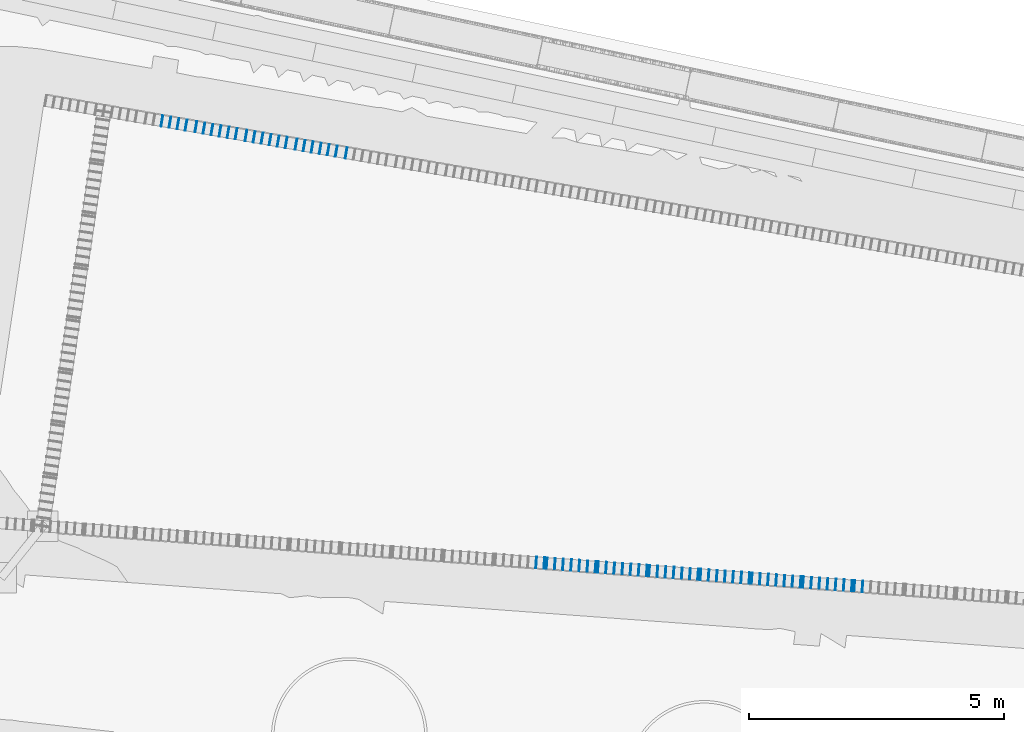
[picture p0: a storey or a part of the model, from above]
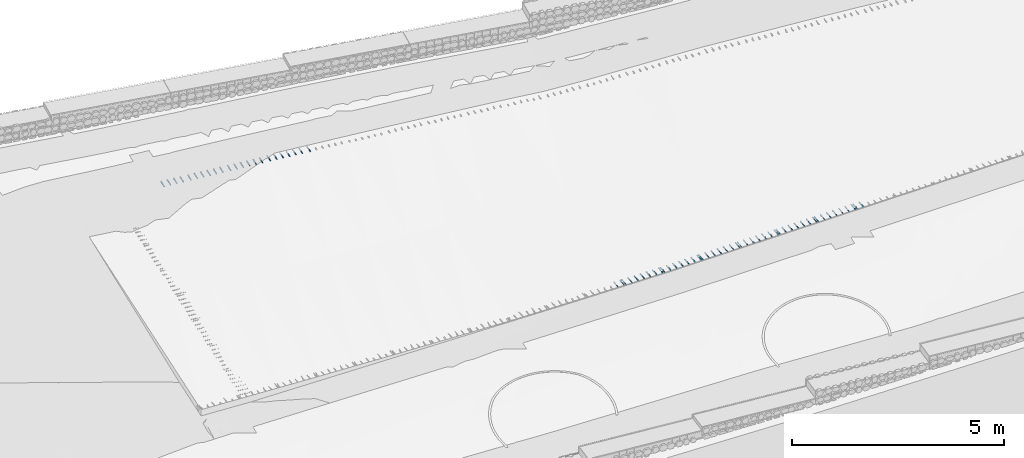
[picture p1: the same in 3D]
Properties of the parts of a building model (IFC4), part 1 of 3

# File
Description: ViewDefinition [CoordinationView]
File name: Casa_Sobreposta_Implantada.ifc
Time: 2026-10-02T14:25:56
Written by: IfcOpenShell 0.8.0
Made in: IfcOpenShell 0.8.0

# IfcProject, Casa / Lares · R08 · Telhado tradicional
Pset_CasaModel - Design: R08 / telha / lower hybrid podium and ground-supported parking; ReferenceFile: 260617_CasaDFL_Estrutura_Terreno.ifc; ModelStatus: DESIGN_STUDY; North: Survey grid +Y; Ramp: No exterior pedestrian ramp or vehicular bridge; EngineeringStatus: Member sizes, foundations, connections, bracing and environmental performance not verified; GroundFFL_m: 14.65; AreaLimit_m2: 250; CountedGeometricArea_m2: 163.712; GreenhouseExcludedByUser: no; BalconiesExcludedByClient: yes; CoveredGroundBalcony_m2: 132.714; PlanningComplianceEstablished: no; AreaBasis: Client-confirmed 250 m2 allowance: parking, cistern, balconies and open greenhouse excluded; enclosed upper rooms and stair enclosures count. Any storage would count. Geometric study, no independent PDM verification.

# IfcSite, Lares · Rua das Mercês · artigo 4771
Pset_SurveySource - File: GN_09.26_213 Lares.dwg; SHA256: 0bca0a0751148bad1398f92d81b795428f94a57fea5e37dec0e125cea70402a1; Area_m2: 1636.5; BoundaryHandle: 31B; CoordinateReference: PT-TM06 / ETRS89; TerrainStatus: Proposed grading; original survey in separate IFC

# IfcBuilding, Casa Sobreposta
Pset_CasaPlacement - GroundFloorSurveyLevel_m: 14.65; UpperFloor: no; MoveEast_m: 3; MoveSouth_m: 0.5; RotationFromGridEast_deg: -8.5; BoundarySetbackRequired_m: 3; RuleBasis: User project constraint
Pset_CasaRevision08 - Variant: telha; HybridPodium: yes; ParkingGroundSupported: yes; GroundFFL_m: 14.65; TerraceFFL_m: 14.61; VehicularBridgeLength_m: 0; AccessGabions: no; Cut_m3: 106.804; Fill_m3: 2.37597; EarthworkExclusions: Topsoil, foundation/service trenches, soil replacement, construction working space and bulking; CoveredGroundBalconyClassification: EXCLUDED_BY_CLIENT; WindCapacityVerified: no

# IfcBuildingStorey (2)
In: Casa Sobreposta
Name | Elevation (m)
00 · Habitação e estacionamento | 14.65
-01 · Cisterna sob o terraço | 12.05

# IfcSpace (11)
In: 00 · Habitação e estacionamento
Pset_CasaProvenance - DesignSource: Casa Sobreposta / configuration.json; ReferenceFile: 260617_CasaDFL_Estrutura_Terreno.ifc; ConstructionBasis: DESIGN_ASSUMPTION; Note: Functional zone from configurator; overlaps with partition footprints removed on ground floor. Not certified usable floor area.
Name | PredefinedType | NetFloorArea (m2)
Sala | INTERNAL | 31.359
Cozinha | INTERNAL | 9.94248
Banho | INTERNAL | 7.19804
WC | INTERNAL | 1.231
Serviço | INTERNAL | 4.16058
Acesso IS | INTERNAL | 3.99017
Quarto 1 | INTERNAL | 13.1145
Quarto 2 | INTERNAL | 13.1145
Quarto / escritório | INTERNAL | 37.8909
Circulação | INTERNAL | 18.1139
Estacionamento · 2 lugares | EXTERNAL | 32.55

# IfcAnnotation (4)
Pset_CasaProvenance - DesignSource: Casa Sobreposta / configuration.json; ReferenceFile: 260617_CasaDFL_Estrutura_Terreno.ifc; ConstructionBasis: DESIGN_ASSUMPTION
Name | In
Lugar P1 · 2.50 x 5.00 m | 00 · Habitação e estacionamento
Lugar P2 · 2.50 x 5.00 m | 00 · Habitação e estacionamento
Limite levantado · 31B | Lares · Rua das Mercês · artigo 4771
Afastamento de implantação · 3 m | Lares · Rua das Mercês · artigo 4771

# IfcBeam (11)
In: 00 · Habitação e estacionamento
Material: Betão armado / Stahlbeton
Pset_CasaProvenance - DesignSource: Casa Sobreposta / configuration.json; ReferenceFile: 260617_CasaDFL_Estrutura_Terreno.ifc; ConstructionBasis: DESIGN_ASSUMPTION
Name
8 x Pódio suspenso · viga transversal
3 x Pódio suspenso · viga longitudinal

# IfcBeam: TIMBER0.140x0.220 / timber (5)
In: 00 · Habitação e estacionamento
Type - Material: Madeira / Bauholz
Pset_CasaProvenance - DesignSource: Casa Sobreposta / configuration.json; ReferenceFile: 260617_CasaDFL_Estrutura_Terreno.ifc; ConstructionBasis: DESIGN_ASSUMPTION; Note: Visible timber concept; strength class, deflection, stability, wind and fire design pending.

# IfcBeam: TIMBER0.160x0.220 / timber (4)
In: 00 · Habitação e estacionamento
Type - Material: Madeira / Bauholz
Pset_CasaProvenance - DesignSource: Casa Sobreposta / configuration.json; ReferenceFile: 260617_CasaDFL_Estrutura_Terreno.ifc; ConstructionBasis: DESIGN_ASSUMPTION; Note: Visible timber concept; strength class, deflection, stability, wind and fire design pending.
Name
2 x Cobertura · frechal longitudinal
2 x Varanda coberta · frechal

# IfcBeam: TIMBER0.160x0.240 / timber (12)
In: 00 · Habitação e estacionamento
Type - Material: Madeira / Bauholz
Pset_CasaProvenance - DesignSource: Casa Sobreposta / configuration.json; ReferenceFile: 260617_CasaDFL_Estrutura_Terreno.ifc; ConstructionBasis: DESIGN_ASSUMPTION; Note: Visible timber concept; strength class, deflection, stability, wind and fire design pending.

# IfcBuildingElementProxy: Acesso · caixa de retenção de sedimentos (2)
In: Lares · Rua das Mercês · artigo 4771
PredefinedType: USERDEFINED; Material: Caleiras · betão
Pset_CasaProvenance - DesignSource: Casa Sobreposta / configuration.json; ReferenceFile: 260617_CasaDFL_Estrutura_Terreno.ifc; ConstructionBasis: DESIGN_ASSUMPTION

# IfcBuildingElementProxy: Acesso · dreno lateral raso · leito drenante (74)
In: Lares · Rua das Mercês · artigo 4771
PredefinedType: USERDEFINED; Material: Brita drenante
Pset_CasaProvenance - DesignSource: Casa Sobreposta / configuration.json; ReferenceFile: 260617_CasaDFL_Estrutura_Terreno.ifc; ConstructionBasis: DESIGN_ASSUMPTION; Note: R08 concept geometry; dimensions and connections not structurally verified.

# IfcBuildingElementProxy: Cisterna · água a 2,00 m, hipótese
In: -01 · Cisterna sob o terraço
PredefinedType: USERDEFINED; Material: Água pluvial · nível ilustrativo
Pset_CasaProvenance - DesignSource: Casa Sobreposta / configuration.json; ReferenceFile: 260617_CasaDFL_Estrutura_Terreno.ifc; ConstructionBasis: DESIGN_ASSUMPTION; Note: Illustrative water envelope, not concrete or a certified operating capacity.

# IfcBuildingElementProxy: Cobertura · caleira pluvial para cisterna (2)
In: 00 · Habitação e estacionamento
PredefinedType: USERDEFINED; Material: Aço galvanizado / Stahl verzinkt
Pset_CasaProvenance - DesignSource: Casa Sobreposta / configuration.json; ReferenceFile: 260617_CasaDFL_Estrutura_Terreno.ifc; ConstructionBasis: DESIGN_ASSUMPTION

# IfcBuildingElementProxy: Interceção · caleira estacionamento · leito drenante (8)
In: Lares · Rua das Mercês · artigo 4771
PredefinedType: USERDEFINED; Material: Brita drenante
Pset_CasaProvenance - DesignSource: Casa Sobreposta / configuration.json; ReferenceFile: 260617_CasaDFL_Estrutura_Terreno.ifc; ConstructionBasis: DESIGN_ASSUMPTION; Note: R08 concept geometry; dimensions and connections not structurally verified.

# IfcBuildingElementProxy: Interceção · caleira rua · leito drenante (8)
In: Lares · Rua das Mercês · artigo 4771
PredefinedType: USERDEFINED; Material: Brita drenante
Pset_CasaProvenance - DesignSource: Casa Sobreposta / configuration.json; ReferenceFile: 260617_CasaDFL_Estrutura_Terreno.ifc; ConstructionBasis: DESIGN_ASSUMPTION; Note: R08 concept geometry; dimensions and connections not structurally verified.

# IfcBuildingElementProxy: Limite north · gabião 10 · cesto galvanizado
In: Lares · Rua das Mercês · artigo 4771
PredefinedType: USERDEFINED; Material: Aço galvanizado / Stahl verzinkt
Pset_CasaProvenance - DesignSource: Casa Sobreposta / configuration.json; ReferenceFile: 260617_CasaDFL_Estrutura_Terreno.ifc; ConstructionBasis: DESIGN_ASSUMPTION; Note: R08 concept geometry; dimensions and connections not structurally verified.

# IfcBuildingElementProxy: Limite north · gabião 10 · pedra aparente
In: Lares · Rua das Mercês · artigo 4771
PredefinedType: USERDEFINED; Material: Gabião · pedra irregular
Pset_CasaProvenance - DesignSource: Casa Sobreposta / configuration.json; ReferenceFile: 260617_CasaDFL_Estrutura_Terreno.ifc; ConstructionBasis: DESIGN_ASSUMPTION; Note: R08 concept geometry; dimensions and connections not structurally verified.

# IfcBuildingElementProxy: Limite north · gabião 11 · cesto galvanizado
In: Lares · Rua das Mercês · artigo 4771
PredefinedType: USERDEFINED; Material: Aço galvanizado / Stahl verzinkt
Pset_CasaProvenance - DesignSource: Casa Sobreposta / configuration.json; ReferenceFile: 260617_CasaDFL_Estrutura_Terreno.ifc; ConstructionBasis: DESIGN_ASSUMPTION; Note: R08 concept geometry; dimensions and connections not structurally verified.

# IfcBuildingElementProxy: Limite north · gabião 11 · pedra aparente
In: Lares · Rua das Mercês · artigo 4771
PredefinedType: USERDEFINED; Material: Gabião · pedra irregular
Pset_CasaProvenance - DesignSource: Casa Sobreposta / configuration.json; ReferenceFile: 260617_CasaDFL_Estrutura_Terreno.ifc; ConstructionBasis: DESIGN_ASSUMPTION; Note: R08 concept geometry; dimensions and connections not structurally verified.

# IfcBuildingElementProxy: Limite north · gabião 12 · cesto galvanizado
In: Lares · Rua das Mercês · artigo 4771
PredefinedType: USERDEFINED; Material: Aço galvanizado / Stahl verzinkt
Pset_CasaProvenance - DesignSource: Casa Sobreposta / configuration.json; ReferenceFile: 260617_CasaDFL_Estrutura_Terreno.ifc; ConstructionBasis: DESIGN_ASSUMPTION; Note: R08 concept geometry; dimensions and connections not structurally verified.

# IfcBuildingElementProxy: Limite north · gabião 12 · pedra aparente
In: Lares · Rua das Mercês · artigo 4771
PredefinedType: USERDEFINED; Material: Gabião · pedra irregular
Pset_CasaProvenance - DesignSource: Casa Sobreposta / configuration.json; ReferenceFile: 260617_CasaDFL_Estrutura_Terreno.ifc; ConstructionBasis: DESIGN_ASSUMPTION; Note: R08 concept geometry; dimensions and connections not structurally verified.

# IfcBuildingElementProxy: Limite north · gabião 13 · cesto galvanizado
In: Lares · Rua das Mercês · artigo 4771
PredefinedType: USERDEFINED; Material: Aço galvanizado / Stahl verzinkt
Pset_CasaProvenance - DesignSource: Casa Sobreposta / configuration.json; ReferenceFile: 260617_CasaDFL_Estrutura_Terreno.ifc; ConstructionBasis: DESIGN_ASSUMPTION; Note: R08 concept geometry; dimensions and connections not structurally verified.

# IfcBuildingElementProxy: Limite north · gabião 13 · pedra aparente
In: Lares · Rua das Mercês · artigo 4771
PredefinedType: USERDEFINED; Material: Gabião · pedra irregular
Pset_CasaProvenance - DesignSource: Casa Sobreposta / configuration.json; ReferenceFile: 260617_CasaDFL_Estrutura_Terreno.ifc; ConstructionBasis: DESIGN_ASSUMPTION; Note: R08 concept geometry; dimensions and connections not structurally verified.

# IfcBuildingElementProxy: Limite north · gabião 14 · cesto galvanizado
In: Lares · Rua das Mercês · artigo 4771
PredefinedType: USERDEFINED; Material: Aço galvanizado / Stahl verzinkt
Pset_CasaProvenance - DesignSource: Casa Sobreposta / configuration.json; ReferenceFile: 260617_CasaDFL_Estrutura_Terreno.ifc; ConstructionBasis: DESIGN_ASSUMPTION; Note: R08 concept geometry; dimensions and connections not structurally verified.

# IfcBuildingElementProxy: Limite north · gabião 14 · pedra aparente
In: Lares · Rua das Mercês · artigo 4771
PredefinedType: USERDEFINED; Material: Gabião · pedra irregular
Pset_CasaProvenance - DesignSource: Casa Sobreposta / configuration.json; ReferenceFile: 260617_CasaDFL_Estrutura_Terreno.ifc; ConstructionBasis: DESIGN_ASSUMPTION; Note: R08 concept geometry; dimensions and connections not structurally verified.

# IfcBuildingElementProxy: Limite north · gabião 15 · cesto galvanizado
In: Lares · Rua das Mercês · artigo 4771
PredefinedType: USERDEFINED; Material: Aço galvanizado / Stahl verzinkt
Pset_CasaProvenance - DesignSource: Casa Sobreposta / configuration.json; ReferenceFile: 260617_CasaDFL_Estrutura_Terreno.ifc; ConstructionBasis: DESIGN_ASSUMPTION; Note: R08 concept geometry; dimensions and connections not structurally verified.

# IfcBuildingElementProxy: Limite north · gabião 15 · pedra aparente
In: Lares · Rua das Mercês · artigo 4771
PredefinedType: USERDEFINED; Material: Gabião · pedra irregular
Pset_CasaProvenance - DesignSource: Casa Sobreposta / configuration.json; ReferenceFile: 260617_CasaDFL_Estrutura_Terreno.ifc; ConstructionBasis: DESIGN_ASSUMPTION; Note: R08 concept geometry; dimensions and connections not structurally verified.

# IfcBuildingElementProxy: Limite north · gabião 16 · cesto galvanizado
In: Lares · Rua das Mercês · artigo 4771
PredefinedType: USERDEFINED; Material: Aço galvanizado / Stahl verzinkt
Pset_CasaProvenance - DesignSource: Casa Sobreposta / configuration.json; ReferenceFile: 260617_CasaDFL_Estrutura_Terreno.ifc; ConstructionBasis: DESIGN_ASSUMPTION; Note: R08 concept geometry; dimensions and connections not structurally verified.

# IfcBuildingElementProxy: Limite north · gabião 16 · pedra aparente
In: Lares · Rua das Mercês · artigo 4771
PredefinedType: USERDEFINED; Material: Gabião · pedra irregular
Pset_CasaProvenance - DesignSource: Casa Sobreposta / configuration.json; ReferenceFile: 260617_CasaDFL_Estrutura_Terreno.ifc; ConstructionBasis: DESIGN_ASSUMPTION; Note: R08 concept geometry; dimensions and connections not structurally verified.

# IfcBuildingElementProxy: Limite north · gabião 17 · cesto galvanizado
In: Lares · Rua das Mercês · artigo 4771
PredefinedType: USERDEFINED; Material: Aço galvanizado / Stahl verzinkt
Pset_CasaProvenance - DesignSource: Casa Sobreposta / configuration.json; ReferenceFile: 260617_CasaDFL_Estrutura_Terreno.ifc; ConstructionBasis: DESIGN_ASSUMPTION; Note: R08 concept geometry; dimensions and connections not structurally verified.

# IfcBuildingElementProxy: Limite north · gabião 17 · pedra aparente
In: Lares · Rua das Mercês · artigo 4771
PredefinedType: USERDEFINED; Material: Gabião · pedra irregular
Pset_CasaProvenance - DesignSource: Casa Sobreposta / configuration.json; ReferenceFile: 260617_CasaDFL_Estrutura_Terreno.ifc; ConstructionBasis: DESIGN_ASSUMPTION; Note: R08 concept geometry; dimensions and connections not structurally verified.

# IfcBuildingElementProxy: Limite north · gabião 18 · cesto galvanizado
In: Lares · Rua das Mercês · artigo 4771
PredefinedType: USERDEFINED; Material: Aço galvanizado / Stahl verzinkt
Pset_CasaProvenance - DesignSource: Casa Sobreposta / configuration.json; ReferenceFile: 260617_CasaDFL_Estrutura_Terreno.ifc; ConstructionBasis: DESIGN_ASSUMPTION; Note: R08 concept geometry; dimensions and connections not structurally verified.

# IfcBuildingElementProxy: Limite north · gabião 18 · pedra aparente
In: Lares · Rua das Mercês · artigo 4771
PredefinedType: USERDEFINED; Material: Gabião · pedra irregular
Pset_CasaProvenance - DesignSource: Casa Sobreposta / configuration.json; ReferenceFile: 260617_CasaDFL_Estrutura_Terreno.ifc; ConstructionBasis: DESIGN_ASSUMPTION; Note: R08 concept geometry; dimensions and connections not structurally verified.

# IfcBuildingElementProxy: Limite north · gabião 19 · cesto galvanizado
In: Lares · Rua das Mercês · artigo 4771
PredefinedType: USERDEFINED; Material: Aço galvanizado / Stahl verzinkt
Pset_CasaProvenance - DesignSource: Casa Sobreposta / configuration.json; ReferenceFile: 260617_CasaDFL_Estrutura_Terreno.ifc; ConstructionBasis: DESIGN_ASSUMPTION; Note: R08 concept geometry; dimensions and connections not structurally verified.

# IfcBuildingElementProxy: Limite north · gabião 19 · pedra aparente
In: Lares · Rua das Mercês · artigo 4771
PredefinedType: USERDEFINED; Material: Gabião · pedra irregular
Pset_CasaProvenance - DesignSource: Casa Sobreposta / configuration.json; ReferenceFile: 260617_CasaDFL_Estrutura_Terreno.ifc; ConstructionBasis: DESIGN_ASSUMPTION; Note: R08 concept geometry; dimensions and connections not structurally verified.

# IfcBuildingElementProxy: Limite north · gabião 20 · cesto galvanizado
In: Lares · Rua das Mercês · artigo 4771
PredefinedType: USERDEFINED; Material: Aço galvanizado / Stahl verzinkt
Pset_CasaProvenance - DesignSource: Casa Sobreposta / configuration.json; ReferenceFile: 260617_CasaDFL_Estrutura_Terreno.ifc; ConstructionBasis: DESIGN_ASSUMPTION; Note: R08 concept geometry; dimensions and connections not structurally verified.

# IfcBuildingElementProxy: Limite north · gabião 20 · pedra aparente
In: Lares · Rua das Mercês · artigo 4771
PredefinedType: USERDEFINED; Material: Gabião · pedra irregular
Pset_CasaProvenance - DesignSource: Casa Sobreposta / configuration.json; ReferenceFile: 260617_CasaDFL_Estrutura_Terreno.ifc; ConstructionBasis: DESIGN_ASSUMPTION; Note: R08 concept geometry; dimensions and connections not structurally verified.

# IfcBuildingElementProxy: Limite north · gabião 21 · cesto galvanizado
In: Lares · Rua das Mercês · artigo 4771
PredefinedType: USERDEFINED; Material: Aço galvanizado / Stahl verzinkt
Pset_CasaProvenance - DesignSource: Casa Sobreposta / configuration.json; ReferenceFile: 260617_CasaDFL_Estrutura_Terreno.ifc; ConstructionBasis: DESIGN_ASSUMPTION; Note: R08 concept geometry; dimensions and connections not structurally verified.

# IfcBuildingElementProxy: Limite north · gabião 21 · pedra aparente
In: Lares · Rua das Mercês · artigo 4771
PredefinedType: USERDEFINED; Material: Gabião · pedra irregular
Pset_CasaProvenance - DesignSource: Casa Sobreposta / configuration.json; ReferenceFile: 260617_CasaDFL_Estrutura_Terreno.ifc; ConstructionBasis: DESIGN_ASSUMPTION; Note: R08 concept geometry; dimensions and connections not structurally verified.

# IfcBuildingElementProxy: Limite north · gabião 22 · cesto galvanizado
In: Lares · Rua das Mercês · artigo 4771
PredefinedType: USERDEFINED; Material: Aço galvanizado / Stahl verzinkt
Pset_CasaProvenance - DesignSource: Casa Sobreposta / configuration.json; ReferenceFile: 260617_CasaDFL_Estrutura_Terreno.ifc; ConstructionBasis: DESIGN_ASSUMPTION; Note: R08 concept geometry; dimensions and connections not structurally verified.

# IfcBuildingElementProxy: Limite north · gabião 22 · pedra aparente
In: Lares · Rua das Mercês · artigo 4771
PredefinedType: USERDEFINED; Material: Gabião · pedra irregular
Pset_CasaProvenance - DesignSource: Casa Sobreposta / configuration.json; ReferenceFile: 260617_CasaDFL_Estrutura_Terreno.ifc; ConstructionBasis: DESIGN_ASSUMPTION; Note: R08 concept geometry; dimensions and connections not structurally verified.

# IfcBuildingElementProxy: Limite north · gabião 23 · cesto galvanizado
In: Lares · Rua das Mercês · artigo 4771
PredefinedType: USERDEFINED; Material: Aço galvanizado / Stahl verzinkt
Pset_CasaProvenance - DesignSource: Casa Sobreposta / configuration.json; ReferenceFile: 260617_CasaDFL_Estrutura_Terreno.ifc; ConstructionBasis: DESIGN_ASSUMPTION; Note: R08 concept geometry; dimensions and connections not structurally verified.

# IfcBuildingElementProxy: Limite north · gabião 23 · pedra aparente
In: Lares · Rua das Mercês · artigo 4771
PredefinedType: USERDEFINED; Material: Gabião · pedra irregular
Pset_CasaProvenance - DesignSource: Casa Sobreposta / configuration.json; ReferenceFile: 260617_CasaDFL_Estrutura_Terreno.ifc; ConstructionBasis: DESIGN_ASSUMPTION; Note: R08 concept geometry; dimensions and connections not structurally verified.

# IfcBuildingElementProxy: Limite north · gabião 24 · cesto galvanizado
In: Lares · Rua das Mercês · artigo 4771
PredefinedType: USERDEFINED; Material: Aço galvanizado / Stahl verzinkt
Pset_CasaProvenance - DesignSource: Casa Sobreposta / configuration.json; ReferenceFile: 260617_CasaDFL_Estrutura_Terreno.ifc; ConstructionBasis: DESIGN_ASSUMPTION; Note: R08 concept geometry; dimensions and connections not structurally verified.

# IfcBuildingElementProxy: Limite north · gabião 24 · pedra aparente
In: Lares · Rua das Mercês · artigo 4771
PredefinedType: USERDEFINED; Material: Gabião · pedra irregular
Pset_CasaProvenance - DesignSource: Casa Sobreposta / configuration.json; ReferenceFile: 260617_CasaDFL_Estrutura_Terreno.ifc; ConstructionBasis: DESIGN_ASSUMPTION; Note: R08 concept geometry; dimensions and connections not structurally verified.

# IfcBuildingElementProxy: Limite north · gabião 25 · cesto galvanizado
In: Lares · Rua das Mercês · artigo 4771
PredefinedType: USERDEFINED; Material: Aço galvanizado / Stahl verzinkt
Pset_CasaProvenance - DesignSource: Casa Sobreposta / configuration.json; ReferenceFile: 260617_CasaDFL_Estrutura_Terreno.ifc; ConstructionBasis: DESIGN_ASSUMPTION; Note: R08 concept geometry; dimensions and connections not structurally verified.

# IfcBuildingElementProxy: Limite north · gabião 25 · pedra aparente
In: Lares · Rua das Mercês · artigo 4771
PredefinedType: USERDEFINED; Material: Gabião · pedra irregular
Pset_CasaProvenance - DesignSource: Casa Sobreposta / configuration.json; ReferenceFile: 260617_CasaDFL_Estrutura_Terreno.ifc; ConstructionBasis: DESIGN_ASSUMPTION; Note: R08 concept geometry; dimensions and connections not structurally verified.

# IfcBuildingElementProxy: Limite north · gabião 26 · cesto galvanizado
In: Lares · Rua das Mercês · artigo 4771
PredefinedType: USERDEFINED; Material: Aço galvanizado / Stahl verzinkt
Pset_CasaProvenance - DesignSource: Casa Sobreposta / configuration.json; ReferenceFile: 260617_CasaDFL_Estrutura_Terreno.ifc; ConstructionBasis: DESIGN_ASSUMPTION; Note: R08 concept geometry; dimensions and connections not structurally verified.

# IfcBuildingElementProxy: Limite north · gabião 26 · pedra aparente
In: Lares · Rua das Mercês · artigo 4771
PredefinedType: USERDEFINED; Material: Gabião · pedra irregular
Pset_CasaProvenance - DesignSource: Casa Sobreposta / configuration.json; ReferenceFile: 260617_CasaDFL_Estrutura_Terreno.ifc; ConstructionBasis: DESIGN_ASSUMPTION; Note: R08 concept geometry; dimensions and connections not structurally verified.

# IfcBuildingElementProxy: Limite north · gabião 27 · cesto galvanizado
In: Lares · Rua das Mercês · artigo 4771
PredefinedType: USERDEFINED; Material: Aço galvanizado / Stahl verzinkt
Pset_CasaProvenance - DesignSource: Casa Sobreposta / configuration.json; ReferenceFile: 260617_CasaDFL_Estrutura_Terreno.ifc; ConstructionBasis: DESIGN_ASSUMPTION; Note: R08 concept geometry; dimensions and connections not structurally verified.

# IfcBuildingElementProxy: Limite north · gabião 27 · pedra aparente
In: Lares · Rua das Mercês · artigo 4771
PredefinedType: USERDEFINED; Material: Gabião · pedra irregular
Pset_CasaProvenance - DesignSource: Casa Sobreposta / configuration.json; ReferenceFile: 260617_CasaDFL_Estrutura_Terreno.ifc; ConstructionBasis: DESIGN_ASSUMPTION; Note: R08 concept geometry; dimensions and connections not structurally verified.

# IfcBuildingElementProxy: Limite north · gabião 4 · cesto galvanizado
In: Lares · Rua das Mercês · artigo 4771
PredefinedType: USERDEFINED; Material: Aço galvanizado / Stahl verzinkt
Pset_CasaProvenance - DesignSource: Casa Sobreposta / configuration.json; ReferenceFile: 260617_CasaDFL_Estrutura_Terreno.ifc; ConstructionBasis: DESIGN_ASSUMPTION; Note: R08 concept geometry; dimensions and connections not structurally verified.

# IfcBuildingElementProxy: Limite north · gabião 4 · pedra aparente
In: Lares · Rua das Mercês · artigo 4771
PredefinedType: USERDEFINED; Material: Gabião · pedra irregular
Pset_CasaProvenance - DesignSource: Casa Sobreposta / configuration.json; ReferenceFile: 260617_CasaDFL_Estrutura_Terreno.ifc; ConstructionBasis: DESIGN_ASSUMPTION; Note: R08 concept geometry; dimensions and connections not structurally verified.

# IfcBuildingElementProxy: Limite north · gabião 5 · cesto galvanizado
In: Lares · Rua das Mercês · artigo 4771
PredefinedType: USERDEFINED; Material: Aço galvanizado / Stahl verzinkt
Pset_CasaProvenance - DesignSource: Casa Sobreposta / configuration.json; ReferenceFile: 260617_CasaDFL_Estrutura_Terreno.ifc; ConstructionBasis: DESIGN_ASSUMPTION; Note: R08 concept geometry; dimensions and connections not structurally verified.

# IfcBuildingElementProxy: Limite north · gabião 5 · pedra aparente
In: Lares · Rua das Mercês · artigo 4771
PredefinedType: USERDEFINED; Material: Gabião · pedra irregular
Pset_CasaProvenance - DesignSource: Casa Sobreposta / configuration.json; ReferenceFile: 260617_CasaDFL_Estrutura_Terreno.ifc; ConstructionBasis: DESIGN_ASSUMPTION; Note: R08 concept geometry; dimensions and connections not structurally verified.

# IfcBuildingElementProxy: Limite north · gabião 6 · cesto galvanizado
In: Lares · Rua das Mercês · artigo 4771
PredefinedType: USERDEFINED; Material: Aço galvanizado / Stahl verzinkt
Pset_CasaProvenance - DesignSource: Casa Sobreposta / configuration.json; ReferenceFile: 260617_CasaDFL_Estrutura_Terreno.ifc; ConstructionBasis: DESIGN_ASSUMPTION; Note: R08 concept geometry; dimensions and connections not structurally verified.

# IfcBuildingElementProxy: Limite north · gabião 6 · pedra aparente
In: Lares · Rua das Mercês · artigo 4771
PredefinedType: USERDEFINED; Material: Gabião · pedra irregular
Pset_CasaProvenance - DesignSource: Casa Sobreposta / configuration.json; ReferenceFile: 260617_CasaDFL_Estrutura_Terreno.ifc; ConstructionBasis: DESIGN_ASSUMPTION; Note: R08 concept geometry; dimensions and connections not structurally verified.

# IfcBuildingElementProxy: Limite north · gabião 7 · cesto galvanizado
In: Lares · Rua das Mercês · artigo 4771
PredefinedType: USERDEFINED; Material: Aço galvanizado / Stahl verzinkt
Pset_CasaProvenance - DesignSource: Casa Sobreposta / configuration.json; ReferenceFile: 260617_CasaDFL_Estrutura_Terreno.ifc; ConstructionBasis: DESIGN_ASSUMPTION; Note: R08 concept geometry; dimensions and connections not structurally verified.

# IfcBuildingElementProxy: Limite north · gabião 7 · pedra aparente
In: Lares · Rua das Mercês · artigo 4771
PredefinedType: USERDEFINED; Material: Gabião · pedra irregular
Pset_CasaProvenance - DesignSource: Casa Sobreposta / configuration.json; ReferenceFile: 260617_CasaDFL_Estrutura_Terreno.ifc; ConstructionBasis: DESIGN_ASSUMPTION; Note: R08 concept geometry; dimensions and connections not structurally verified.

# IfcBuildingElementProxy: Limite north · gabião 8 · cesto galvanizado
In: Lares · Rua das Mercês · artigo 4771
PredefinedType: USERDEFINED; Material: Aço galvanizado / Stahl verzinkt
Pset_CasaProvenance - DesignSource: Casa Sobreposta / configuration.json; ReferenceFile: 260617_CasaDFL_Estrutura_Terreno.ifc; ConstructionBasis: DESIGN_ASSUMPTION; Note: R08 concept geometry; dimensions and connections not structurally verified.

# IfcBuildingElementProxy: Limite north · gabião 8 · pedra aparente
In: Lares · Rua das Mercês · artigo 4771
PredefinedType: USERDEFINED; Material: Gabião · pedra irregular
Pset_CasaProvenance - DesignSource: Casa Sobreposta / configuration.json; ReferenceFile: 260617_CasaDFL_Estrutura_Terreno.ifc; ConstructionBasis: DESIGN_ASSUMPTION; Note: R08 concept geometry; dimensions and connections not structurally verified.

# IfcBuildingElementProxy: Limite north · gabião 9 · cesto galvanizado
In: Lares · Rua das Mercês · artigo 4771
PredefinedType: USERDEFINED; Material: Aço galvanizado / Stahl verzinkt
Pset_CasaProvenance - DesignSource: Casa Sobreposta / configuration.json; ReferenceFile: 260617_CasaDFL_Estrutura_Terreno.ifc; ConstructionBasis: DESIGN_ASSUMPTION; Note: R08 concept geometry; dimensions and connections not structurally verified.

# IfcBuildingElementProxy: Limite north · gabião 9 · pedra aparente
In: Lares · Rua das Mercês · artigo 4771
PredefinedType: USERDEFINED; Material: Gabião · pedra irregular
Pset_CasaProvenance - DesignSource: Casa Sobreposta / configuration.json; ReferenceFile: 260617_CasaDFL_Estrutura_Terreno.ifc; ConstructionBasis: DESIGN_ASSUMPTION; Note: R08 concept geometry; dimensions and connections not structurally verified.

# IfcBuildingElementProxy: Limite north · vala de interceção (37)
In: Lares · Rua das Mercês · artigo 4771
PredefinedType: USERDEFINED; Material: Brita drenante
Pset_CasaProvenance - DesignSource: Casa Sobreposta / configuration.json; ReferenceFile: 260617_CasaDFL_Estrutura_Terreno.ifc; ConstructionBasis: DESIGN_ASSUMPTION

# IfcBuildingElementProxy: Limite south · gabião 1 · cesto galvanizado
In: Lares · Rua das Mercês · artigo 4771
PredefinedType: USERDEFINED; Material: Aço galvanizado / Stahl verzinkt
Pset_CasaProvenance - DesignSource: Casa Sobreposta / configuration.json; ReferenceFile: 260617_CasaDFL_Estrutura_Terreno.ifc; ConstructionBasis: DESIGN_ASSUMPTION; Note: R08 concept geometry; dimensions and connections not structurally verified.

# IfcBuildingElementProxy: Limite south · gabião 1 · pedra aparente
In: Lares · Rua das Mercês · artigo 4771
PredefinedType: USERDEFINED; Material: Gabião · pedra irregular
Pset_CasaProvenance - DesignSource: Casa Sobreposta / configuration.json; ReferenceFile: 260617_CasaDFL_Estrutura_Terreno.ifc; ConstructionBasis: DESIGN_ASSUMPTION; Note: R08 concept geometry; dimensions and connections not structurally verified.

# IfcBuildingElementProxy: Limite south · gabião 10 · cesto galvanizado
In: Lares · Rua das Mercês · artigo 4771
PredefinedType: USERDEFINED; Material: Aço galvanizado / Stahl verzinkt
Pset_CasaProvenance - DesignSource: Casa Sobreposta / configuration.json; ReferenceFile: 260617_CasaDFL_Estrutura_Terreno.ifc; ConstructionBasis: DESIGN_ASSUMPTION; Note: R08 concept geometry; dimensions and connections not structurally verified.

# IfcBuildingElementProxy: Limite south · gabião 10 · pedra aparente
In: Lares · Rua das Mercês · artigo 4771
PredefinedType: USERDEFINED; Material: Gabião · pedra irregular
Pset_CasaProvenance - DesignSource: Casa Sobreposta / configuration.json; ReferenceFile: 260617_CasaDFL_Estrutura_Terreno.ifc; ConstructionBasis: DESIGN_ASSUMPTION; Note: R08 concept geometry; dimensions and connections not structurally verified.

# IfcBuildingElementProxy: Limite south · gabião 11 · cesto galvanizado
In: Lares · Rua das Mercês · artigo 4771
PredefinedType: USERDEFINED; Material: Aço galvanizado / Stahl verzinkt
Pset_CasaProvenance - DesignSource: Casa Sobreposta / configuration.json; ReferenceFile: 260617_CasaDFL_Estrutura_Terreno.ifc; ConstructionBasis: DESIGN_ASSUMPTION; Note: R08 concept geometry; dimensions and connections not structurally verified.

# IfcBuildingElementProxy: Limite south · gabião 11 · pedra aparente
In: Lares · Rua das Mercês · artigo 4771
PredefinedType: USERDEFINED; Material: Gabião · pedra irregular
Pset_CasaProvenance - DesignSource: Casa Sobreposta / configuration.json; ReferenceFile: 260617_CasaDFL_Estrutura_Terreno.ifc; ConstructionBasis: DESIGN_ASSUMPTION; Note: R08 concept geometry; dimensions and connections not structurally verified.

# IfcBuildingElementProxy: Limite south · gabião 12 · cesto galvanizado
In: Lares · Rua das Mercês · artigo 4771
PredefinedType: USERDEFINED; Material: Aço galvanizado / Stahl verzinkt
Pset_CasaProvenance - DesignSource: Casa Sobreposta / configuration.json; ReferenceFile: 260617_CasaDFL_Estrutura_Terreno.ifc; ConstructionBasis: DESIGN_ASSUMPTION; Note: R08 concept geometry; dimensions and connections not structurally verified.

# IfcBuildingElementProxy: Limite south · gabião 12 · pedra aparente
In: Lares · Rua das Mercês · artigo 4771
PredefinedType: USERDEFINED; Material: Gabião · pedra irregular
Pset_CasaProvenance - DesignSource: Casa Sobreposta / configuration.json; ReferenceFile: 260617_CasaDFL_Estrutura_Terreno.ifc; ConstructionBasis: DESIGN_ASSUMPTION; Note: R08 concept geometry; dimensions and connections not structurally verified.

# IfcBuildingElementProxy: Limite south · gabião 13 · cesto galvanizado
In: Lares · Rua das Mercês · artigo 4771
PredefinedType: USERDEFINED; Material: Aço galvanizado / Stahl verzinkt
Pset_CasaProvenance - DesignSource: Casa Sobreposta / configuration.json; ReferenceFile: 260617_CasaDFL_Estrutura_Terreno.ifc; ConstructionBasis: DESIGN_ASSUMPTION; Note: R08 concept geometry; dimensions and connections not structurally verified.

# IfcBuildingElementProxy: Limite south · gabião 13 · pedra aparente
In: Lares · Rua das Mercês · artigo 4771
PredefinedType: USERDEFINED; Material: Gabião · pedra irregular
Pset_CasaProvenance - DesignSource: Casa Sobreposta / configuration.json; ReferenceFile: 260617_CasaDFL_Estrutura_Terreno.ifc; ConstructionBasis: DESIGN_ASSUMPTION; Note: R08 concept geometry; dimensions and connections not structurally verified.

# IfcBuildingElementProxy: Limite south · gabião 14 · cesto galvanizado
In: Lares · Rua das Mercês · artigo 4771
PredefinedType: USERDEFINED; Material: Aço galvanizado / Stahl verzinkt
Pset_CasaProvenance - DesignSource: Casa Sobreposta / configuration.json; ReferenceFile: 260617_CasaDFL_Estrutura_Terreno.ifc; ConstructionBasis: DESIGN_ASSUMPTION; Note: R08 concept geometry; dimensions and connections not structurally verified.

# IfcBuildingElementProxy: Limite south · gabião 14 · pedra aparente
In: Lares · Rua das Mercês · artigo 4771
PredefinedType: USERDEFINED; Material: Gabião · pedra irregular
Pset_CasaProvenance - DesignSource: Casa Sobreposta / configuration.json; ReferenceFile: 260617_CasaDFL_Estrutura_Terreno.ifc; ConstructionBasis: DESIGN_ASSUMPTION; Note: R08 concept geometry; dimensions and connections not structurally verified.

# IfcBuildingElementProxy: Limite south · gabião 15 · cesto galvanizado
In: Lares · Rua das Mercês · artigo 4771
PredefinedType: USERDEFINED; Material: Aço galvanizado / Stahl verzinkt
Pset_CasaProvenance - DesignSource: Casa Sobreposta / configuration.json; ReferenceFile: 260617_CasaDFL_Estrutura_Terreno.ifc; ConstructionBasis: DESIGN_ASSUMPTION; Note: R08 concept geometry; dimensions and connections not structurally verified.

# IfcBuildingElementProxy: Limite south · gabião 15 · pedra aparente
In: Lares · Rua das Mercês · artigo 4771
PredefinedType: USERDEFINED; Material: Gabião · pedra irregular
Pset_CasaProvenance - DesignSource: Casa Sobreposta / configuration.json; ReferenceFile: 260617_CasaDFL_Estrutura_Terreno.ifc; ConstructionBasis: DESIGN_ASSUMPTION; Note: R08 concept geometry; dimensions and connections not structurally verified.

# IfcBuildingElementProxy: Limite south · gabião 16 · cesto galvanizado
In: Lares · Rua das Mercês · artigo 4771
PredefinedType: USERDEFINED; Material: Aço galvanizado / Stahl verzinkt
Pset_CasaProvenance - DesignSource: Casa Sobreposta / configuration.json; ReferenceFile: 260617_CasaDFL_Estrutura_Terreno.ifc; ConstructionBasis: DESIGN_ASSUMPTION; Note: R08 concept geometry; dimensions and connections not structurally verified.

# IfcBuildingElementProxy: Limite south · gabião 16 · pedra aparente
In: Lares · Rua das Mercês · artigo 4771
PredefinedType: USERDEFINED; Material: Gabião · pedra irregular
Pset_CasaProvenance - DesignSource: Casa Sobreposta / configuration.json; ReferenceFile: 260617_CasaDFL_Estrutura_Terreno.ifc; ConstructionBasis: DESIGN_ASSUMPTION; Note: R08 concept geometry; dimensions and connections not structurally verified.

# IfcBuildingElementProxy: Limite south · gabião 17 · cesto galvanizado
In: Lares · Rua das Mercês · artigo 4771
PredefinedType: USERDEFINED; Material: Aço galvanizado / Stahl verzinkt
Pset_CasaProvenance - DesignSource: Casa Sobreposta / configuration.json; ReferenceFile: 260617_CasaDFL_Estrutura_Terreno.ifc; ConstructionBasis: DESIGN_ASSUMPTION; Note: R08 concept geometry; dimensions and connections not structurally verified.

# IfcBuildingElementProxy: Limite south · gabião 17 · pedra aparente
In: Lares · Rua das Mercês · artigo 4771
PredefinedType: USERDEFINED; Material: Gabião · pedra irregular
Pset_CasaProvenance - DesignSource: Casa Sobreposta / configuration.json; ReferenceFile: 260617_CasaDFL_Estrutura_Terreno.ifc; ConstructionBasis: DESIGN_ASSUMPTION; Note: R08 concept geometry; dimensions and connections not structurally verified.

# IfcBuildingElementProxy: Limite south · gabião 18 · cesto galvanizado
In: Lares · Rua das Mercês · artigo 4771
PredefinedType: USERDEFINED; Material: Aço galvanizado / Stahl verzinkt
Pset_CasaProvenance - DesignSource: Casa Sobreposta / configuration.json; ReferenceFile: 260617_CasaDFL_Estrutura_Terreno.ifc; ConstructionBasis: DESIGN_ASSUMPTION; Note: R08 concept geometry; dimensions and connections not structurally verified.

# IfcBuildingElementProxy: Limite south · gabião 18 · pedra aparente
In: Lares · Rua das Mercês · artigo 4771
PredefinedType: USERDEFINED; Material: Gabião · pedra irregular
Pset_CasaProvenance - DesignSource: Casa Sobreposta / configuration.json; ReferenceFile: 260617_CasaDFL_Estrutura_Terreno.ifc; ConstructionBasis: DESIGN_ASSUMPTION; Note: R08 concept geometry; dimensions and connections not structurally verified.

# IfcBuildingElementProxy: Limite south · gabião 19 · cesto galvanizado
In: Lares · Rua das Mercês · artigo 4771
PredefinedType: USERDEFINED; Material: Aço galvanizado / Stahl verzinkt
Pset_CasaProvenance - DesignSource: Casa Sobreposta / configuration.json; ReferenceFile: 260617_CasaDFL_Estrutura_Terreno.ifc; ConstructionBasis: DESIGN_ASSUMPTION; Note: R08 concept geometry; dimensions and connections not structurally verified.

# IfcBuildingElementProxy: Limite south · gabião 19 · pedra aparente
In: Lares · Rua das Mercês · artigo 4771
PredefinedType: USERDEFINED; Material: Gabião · pedra irregular
Pset_CasaProvenance - DesignSource: Casa Sobreposta / configuration.json; ReferenceFile: 260617_CasaDFL_Estrutura_Terreno.ifc; ConstructionBasis: DESIGN_ASSUMPTION; Note: R08 concept geometry; dimensions and connections not structurally verified.

# IfcBuildingElementProxy: Limite south · gabião 2 · cesto galvanizado
In: Lares · Rua das Mercês · artigo 4771
PredefinedType: USERDEFINED; Material: Aço galvanizado / Stahl verzinkt
Pset_CasaProvenance - DesignSource: Casa Sobreposta / configuration.json; ReferenceFile: 260617_CasaDFL_Estrutura_Terreno.ifc; ConstructionBasis: DESIGN_ASSUMPTION; Note: R08 concept geometry; dimensions and connections not structurally verified.

# IfcBuildingElementProxy: Limite south · gabião 2 · pedra aparente
In: Lares · Rua das Mercês · artigo 4771
PredefinedType: USERDEFINED; Material: Gabião · pedra irregular
Pset_CasaProvenance - DesignSource: Casa Sobreposta / configuration.json; ReferenceFile: 260617_CasaDFL_Estrutura_Terreno.ifc; ConstructionBasis: DESIGN_ASSUMPTION; Note: R08 concept geometry; dimensions and connections not structurally verified.

# IfcBuildingElementProxy: Limite south · gabião 20 · cesto galvanizado
In: Lares · Rua das Mercês · artigo 4771
PredefinedType: USERDEFINED; Material: Aço galvanizado / Stahl verzinkt
Pset_CasaProvenance - DesignSource: Casa Sobreposta / configuration.json; ReferenceFile: 260617_CasaDFL_Estrutura_Terreno.ifc; ConstructionBasis: DESIGN_ASSUMPTION; Note: R08 concept geometry; dimensions and connections not structurally verified.

# IfcBuildingElementProxy: Limite south · gabião 20 · pedra aparente
In: Lares · Rua das Mercês · artigo 4771
PredefinedType: USERDEFINED; Material: Gabião · pedra irregular
Pset_CasaProvenance - DesignSource: Casa Sobreposta / configuration.json; ReferenceFile: 260617_CasaDFL_Estrutura_Terreno.ifc; ConstructionBasis: DESIGN_ASSUMPTION; Note: R08 concept geometry; dimensions and connections not structurally verified.

# IfcBuildingElementProxy: Limite south · gabião 21 · cesto galvanizado
In: Lares · Rua das Mercês · artigo 4771
PredefinedType: USERDEFINED; Material: Aço galvanizado / Stahl verzinkt
Pset_CasaProvenance - DesignSource: Casa Sobreposta / configuration.json; ReferenceFile: 260617_CasaDFL_Estrutura_Terreno.ifc; ConstructionBasis: DESIGN_ASSUMPTION; Note: R08 concept geometry; dimensions and connections not structurally verified.

# IfcBuildingElementProxy: Limite south · gabião 21 · pedra aparente
In: Lares · Rua das Mercês · artigo 4771
PredefinedType: USERDEFINED; Material: Gabião · pedra irregular
Pset_CasaProvenance - DesignSource: Casa Sobreposta / configuration.json; ReferenceFile: 260617_CasaDFL_Estrutura_Terreno.ifc; ConstructionBasis: DESIGN_ASSUMPTION; Note: R08 concept geometry; dimensions and connections not structurally verified.

# IfcBuildingElementProxy: Limite south · gabião 22 · cesto galvanizado
In: Lares · Rua das Mercês · artigo 4771
PredefinedType: USERDEFINED; Material: Aço galvanizado / Stahl verzinkt
Pset_CasaProvenance - DesignSource: Casa Sobreposta / configuration.json; ReferenceFile: 260617_CasaDFL_Estrutura_Terreno.ifc; ConstructionBasis: DESIGN_ASSUMPTION; Note: R08 concept geometry; dimensions and connections not structurally verified.

# IfcBuildingElementProxy: Limite south · gabião 22 · pedra aparente
In: Lares · Rua das Mercês · artigo 4771
PredefinedType: USERDEFINED; Material: Gabião · pedra irregular
Pset_CasaProvenance - DesignSource: Casa Sobreposta / configuration.json; ReferenceFile: 260617_CasaDFL_Estrutura_Terreno.ifc; ConstructionBasis: DESIGN_ASSUMPTION; Note: R08 concept geometry; dimensions and connections not structurally verified.

# IfcBuildingElementProxy: Limite south · gabião 23 · cesto galvanizado
In: Lares · Rua das Mercês · artigo 4771
PredefinedType: USERDEFINED; Material: Aço galvanizado / Stahl verzinkt
Pset_CasaProvenance - DesignSource: Casa Sobreposta / configuration.json; ReferenceFile: 260617_CasaDFL_Estrutura_Terreno.ifc; ConstructionBasis: DESIGN_ASSUMPTION; Note: R08 concept geometry; dimensions and connections not structurally verified.

# IfcBuildingElementProxy: Limite south · gabião 23 · pedra aparente
In: Lares · Rua das Mercês · artigo 4771
PredefinedType: USERDEFINED; Material: Gabião · pedra irregular
Pset_CasaProvenance - DesignSource: Casa Sobreposta / configuration.json; ReferenceFile: 260617_CasaDFL_Estrutura_Terreno.ifc; ConstructionBasis: DESIGN_ASSUMPTION; Note: R08 concept geometry; dimensions and connections not structurally verified.

# IfcBuildingElementProxy: Limite south · gabião 24 · cesto galvanizado
In: Lares · Rua das Mercês · artigo 4771
PredefinedType: USERDEFINED; Material: Aço galvanizado / Stahl verzinkt
Pset_CasaProvenance - DesignSource: Casa Sobreposta / configuration.json; ReferenceFile: 260617_CasaDFL_Estrutura_Terreno.ifc; ConstructionBasis: DESIGN_ASSUMPTION; Note: R08 concept geometry; dimensions and connections not structurally verified.

# IfcBuildingElementProxy: Limite south · gabião 24 · pedra aparente
In: Lares · Rua das Mercês · artigo 4771
PredefinedType: USERDEFINED; Material: Gabião · pedra irregular
Pset_CasaProvenance - DesignSource: Casa Sobreposta / configuration.json; ReferenceFile: 260617_CasaDFL_Estrutura_Terreno.ifc; ConstructionBasis: DESIGN_ASSUMPTION; Note: R08 concept geometry; dimensions and connections not structurally verified.

# IfcBuildingElementProxy: Limite south · gabião 25 · cesto galvanizado
In: Lares · Rua das Mercês · artigo 4771
PredefinedType: USERDEFINED; Material: Aço galvanizado / Stahl verzinkt
Pset_CasaProvenance - DesignSource: Casa Sobreposta / configuration.json; ReferenceFile: 260617_CasaDFL_Estrutura_Terreno.ifc; ConstructionBasis: DESIGN_ASSUMPTION; Note: R08 concept geometry; dimensions and connections not structurally verified.

# IfcBuildingElementProxy: Limite south · gabião 25 · pedra aparente
In: Lares · Rua das Mercês · artigo 4771
PredefinedType: USERDEFINED; Material: Gabião · pedra irregular
Pset_CasaProvenance - DesignSource: Casa Sobreposta / configuration.json; ReferenceFile: 260617_CasaDFL_Estrutura_Terreno.ifc; ConstructionBasis: DESIGN_ASSUMPTION; Note: R08 concept geometry; dimensions and connections not structurally verified.

# IfcBuildingElementProxy: Limite south · gabião 26 · cesto galvanizado
In: Lares · Rua das Mercês · artigo 4771
PredefinedType: USERDEFINED; Material: Aço galvanizado / Stahl verzinkt
Pset_CasaProvenance - DesignSource: Casa Sobreposta / configuration.json; ReferenceFile: 260617_CasaDFL_Estrutura_Terreno.ifc; ConstructionBasis: DESIGN_ASSUMPTION; Note: R08 concept geometry; dimensions and connections not structurally verified.

# IfcBuildingElementProxy: Limite south · gabião 26 · pedra aparente
In: Lares · Rua das Mercês · artigo 4771
PredefinedType: USERDEFINED; Material: Gabião · pedra irregular
Pset_CasaProvenance - DesignSource: Casa Sobreposta / configuration.json; ReferenceFile: 260617_CasaDFL_Estrutura_Terreno.ifc; ConstructionBasis: DESIGN_ASSUMPTION; Note: R08 concept geometry; dimensions and connections not structurally verified.

# IfcBuildingElementProxy: Limite south · gabião 27 · cesto galvanizado
In: Lares · Rua das Mercês · artigo 4771
PredefinedType: USERDEFINED; Material: Aço galvanizado / Stahl verzinkt
Pset_CasaProvenance - DesignSource: Casa Sobreposta / configuration.json; ReferenceFile: 260617_CasaDFL_Estrutura_Terreno.ifc; ConstructionBasis: DESIGN_ASSUMPTION; Note: R08 concept geometry; dimensions and connections not structurally verified.

# IfcBuildingElementProxy: Limite south · gabião 27 · pedra aparente
In: Lares · Rua das Mercês · artigo 4771
PredefinedType: USERDEFINED; Material: Gabião · pedra irregular
Pset_CasaProvenance - DesignSource: Casa Sobreposta / configuration.json; ReferenceFile: 260617_CasaDFL_Estrutura_Terreno.ifc; ConstructionBasis: DESIGN_ASSUMPTION; Note: R08 concept geometry; dimensions and connections not structurally verified.

# IfcBuildingElementProxy: Limite south · gabião 28 · cesto galvanizado
In: Lares · Rua das Mercês · artigo 4771
PredefinedType: USERDEFINED; Material: Aço galvanizado / Stahl verzinkt
Pset_CasaProvenance - DesignSource: Casa Sobreposta / configuration.json; ReferenceFile: 260617_CasaDFL_Estrutura_Terreno.ifc; ConstructionBasis: DESIGN_ASSUMPTION; Note: R08 concept geometry; dimensions and connections not structurally verified.

# IfcBuildingElementProxy: Limite south · gabião 28 · pedra aparente
In: Lares · Rua das Mercês · artigo 4771
PredefinedType: USERDEFINED; Material: Gabião · pedra irregular
Pset_CasaProvenance - DesignSource: Casa Sobreposta / configuration.json; ReferenceFile: 260617_CasaDFL_Estrutura_Terreno.ifc; ConstructionBasis: DESIGN_ASSUMPTION; Note: R08 concept geometry; dimensions and connections not structurally verified.

# IfcBuildingElementProxy: Limite south · gabião 29 · cesto galvanizado
In: Lares · Rua das Mercês · artigo 4771
PredefinedType: USERDEFINED; Material: Aço galvanizado / Stahl verzinkt
Pset_CasaProvenance - DesignSource: Casa Sobreposta / configuration.json; ReferenceFile: 260617_CasaDFL_Estrutura_Terreno.ifc; ConstructionBasis: DESIGN_ASSUMPTION; Note: R08 concept geometry; dimensions and connections not structurally verified.

# IfcBuildingElementProxy: Limite south · gabião 29 · pedra aparente
In: Lares · Rua das Mercês · artigo 4771
PredefinedType: USERDEFINED; Material: Gabião · pedra irregular
Pset_CasaProvenance - DesignSource: Casa Sobreposta / configuration.json; ReferenceFile: 260617_CasaDFL_Estrutura_Terreno.ifc; ConstructionBasis: DESIGN_ASSUMPTION; Note: R08 concept geometry; dimensions and connections not structurally verified.

# IfcBuildingElementProxy: Limite south · gabião 3 · cesto galvanizado
In: Lares · Rua das Mercês · artigo 4771
PredefinedType: USERDEFINED; Material: Aço galvanizado / Stahl verzinkt
Pset_CasaProvenance - DesignSource: Casa Sobreposta / configuration.json; ReferenceFile: 260617_CasaDFL_Estrutura_Terreno.ifc; ConstructionBasis: DESIGN_ASSUMPTION; Note: R08 concept geometry; dimensions and connections not structurally verified.

# IfcBuildingElementProxy: Limite south · gabião 3 · pedra aparente
In: Lares · Rua das Mercês · artigo 4771
PredefinedType: USERDEFINED; Material: Gabião · pedra irregular
Pset_CasaProvenance - DesignSource: Casa Sobreposta / configuration.json; ReferenceFile: 260617_CasaDFL_Estrutura_Terreno.ifc; ConstructionBasis: DESIGN_ASSUMPTION; Note: R08 concept geometry; dimensions and connections not structurally verified.

# IfcBuildingElementProxy: Limite south · gabião 30 · cesto galvanizado
In: Lares · Rua das Mercês · artigo 4771
PredefinedType: USERDEFINED; Material: Aço galvanizado / Stahl verzinkt
Pset_CasaProvenance - DesignSource: Casa Sobreposta / configuration.json; ReferenceFile: 260617_CasaDFL_Estrutura_Terreno.ifc; ConstructionBasis: DESIGN_ASSUMPTION; Note: R08 concept geometry; dimensions and connections not structurally verified.

# IfcBuildingElementProxy: Limite south · gabião 30 · pedra aparente
In: Lares · Rua das Mercês · artigo 4771
PredefinedType: USERDEFINED; Material: Gabião · pedra irregular
Pset_CasaProvenance - DesignSource: Casa Sobreposta / configuration.json; ReferenceFile: 260617_CasaDFL_Estrutura_Terreno.ifc; ConstructionBasis: DESIGN_ASSUMPTION; Note: R08 concept geometry; dimensions and connections not structurally verified.

# IfcBuildingElementProxy: Limite south · gabião 31 · cesto galvanizado
In: Lares · Rua das Mercês · artigo 4771
PredefinedType: USERDEFINED; Material: Aço galvanizado / Stahl verzinkt
Pset_CasaProvenance - DesignSource: Casa Sobreposta / configuration.json; ReferenceFile: 260617_CasaDFL_Estrutura_Terreno.ifc; ConstructionBasis: DESIGN_ASSUMPTION; Note: R08 concept geometry; dimensions and connections not structurally verified.

# IfcBuildingElementProxy: Limite south · gabião 31 · pedra aparente
In: Lares · Rua das Mercês · artigo 4771
PredefinedType: USERDEFINED; Material: Gabião · pedra irregular
Pset_CasaProvenance - DesignSource: Casa Sobreposta / configuration.json; ReferenceFile: 260617_CasaDFL_Estrutura_Terreno.ifc; ConstructionBasis: DESIGN_ASSUMPTION; Note: R08 concept geometry; dimensions and connections not structurally verified.

# IfcBuildingElementProxy: Limite south · gabião 4 · cesto galvanizado
In: Lares · Rua das Mercês · artigo 4771
PredefinedType: USERDEFINED; Material: Aço galvanizado / Stahl verzinkt
Pset_CasaProvenance - DesignSource: Casa Sobreposta / configuration.json; ReferenceFile: 260617_CasaDFL_Estrutura_Terreno.ifc; ConstructionBasis: DESIGN_ASSUMPTION; Note: R08 concept geometry; dimensions and connections not structurally verified.

# IfcBuildingElementProxy: Limite south · gabião 4 · pedra aparente
In: Lares · Rua das Mercês · artigo 4771
PredefinedType: USERDEFINED; Material: Gabião · pedra irregular
Pset_CasaProvenance - DesignSource: Casa Sobreposta / configuration.json; ReferenceFile: 260617_CasaDFL_Estrutura_Terreno.ifc; ConstructionBasis: DESIGN_ASSUMPTION; Note: R08 concept geometry; dimensions and connections not structurally verified.

# IfcBuildingElementProxy: Limite south · gabião 5 · cesto galvanizado
In: Lares · Rua das Mercês · artigo 4771
PredefinedType: USERDEFINED; Material: Aço galvanizado / Stahl verzinkt
Pset_CasaProvenance - DesignSource: Casa Sobreposta / configuration.json; ReferenceFile: 260617_CasaDFL_Estrutura_Terreno.ifc; ConstructionBasis: DESIGN_ASSUMPTION; Note: R08 concept geometry; dimensions and connections not structurally verified.

# IfcBuildingElementProxy: Limite south · gabião 5 · pedra aparente
In: Lares · Rua das Mercês · artigo 4771
PredefinedType: USERDEFINED; Material: Gabião · pedra irregular
Pset_CasaProvenance - DesignSource: Casa Sobreposta / configuration.json; ReferenceFile: 260617_CasaDFL_Estrutura_Terreno.ifc; ConstructionBasis: DESIGN_ASSUMPTION; Note: R08 concept geometry; dimensions and connections not structurally verified.

# IfcBuildingElementProxy: Limite south · gabião 6 · cesto galvanizado
In: Lares · Rua das Mercês · artigo 4771
PredefinedType: USERDEFINED; Material: Aço galvanizado / Stahl verzinkt
Pset_CasaProvenance - DesignSource: Casa Sobreposta / configuration.json; ReferenceFile: 260617_CasaDFL_Estrutura_Terreno.ifc; ConstructionBasis: DESIGN_ASSUMPTION; Note: R08 concept geometry; dimensions and connections not structurally verified.

# IfcBuildingElementProxy: Limite south · gabião 6 · pedra aparente
In: Lares · Rua das Mercês · artigo 4771
PredefinedType: USERDEFINED; Material: Gabião · pedra irregular
Pset_CasaProvenance - DesignSource: Casa Sobreposta / configuration.json; ReferenceFile: 260617_CasaDFL_Estrutura_Terreno.ifc; ConstructionBasis: DESIGN_ASSUMPTION; Note: R08 concept geometry; dimensions and connections not structurally verified.

# IfcBuildingElementProxy: Limite south · gabião 7 · cesto galvanizado
In: Lares · Rua das Mercês · artigo 4771
PredefinedType: USERDEFINED; Material: Aço galvanizado / Stahl verzinkt
Pset_CasaProvenance - DesignSource: Casa Sobreposta / configuration.json; ReferenceFile: 260617_CasaDFL_Estrutura_Terreno.ifc; ConstructionBasis: DESIGN_ASSUMPTION; Note: R08 concept geometry; dimensions and connections not structurally verified.

# IfcBuildingElementProxy: Limite south · gabião 7 · pedra aparente
In: Lares · Rua das Mercês · artigo 4771
PredefinedType: USERDEFINED; Material: Gabião · pedra irregular
Pset_CasaProvenance - DesignSource: Casa Sobreposta / configuration.json; ReferenceFile: 260617_CasaDFL_Estrutura_Terreno.ifc; ConstructionBasis: DESIGN_ASSUMPTION; Note: R08 concept geometry; dimensions and connections not structurally verified.

# IfcBuildingElementProxy: Limite south · gabião 8 · cesto galvanizado
In: Lares · Rua das Mercês · artigo 4771
PredefinedType: USERDEFINED; Material: Aço galvanizado / Stahl verzinkt
Pset_CasaProvenance - DesignSource: Casa Sobreposta / configuration.json; ReferenceFile: 260617_CasaDFL_Estrutura_Terreno.ifc; ConstructionBasis: DESIGN_ASSUMPTION; Note: R08 concept geometry; dimensions and connections not structurally verified.

# IfcBuildingElementProxy: Limite south · gabião 8 · pedra aparente
In: Lares · Rua das Mercês · artigo 4771
PredefinedType: USERDEFINED; Material: Gabião · pedra irregular
Pset_CasaProvenance - DesignSource: Casa Sobreposta / configuration.json; ReferenceFile: 260617_CasaDFL_Estrutura_Terreno.ifc; ConstructionBasis: DESIGN_ASSUMPTION; Note: R08 concept geometry; dimensions and connections not structurally verified.

# IfcBuildingElementProxy: Limite south · gabião 9 · cesto galvanizado
In: Lares · Rua das Mercês · artigo 4771
PredefinedType: USERDEFINED; Material: Aço galvanizado / Stahl verzinkt
Pset_CasaProvenance - DesignSource: Casa Sobreposta / configuration.json; ReferenceFile: 260617_CasaDFL_Estrutura_Terreno.ifc; ConstructionBasis: DESIGN_ASSUMPTION; Note: R08 concept geometry; dimensions and connections not structurally verified.

# IfcBuildingElementProxy: Limite south · gabião 9 · pedra aparente
In: Lares · Rua das Mercês · artigo 4771
PredefinedType: USERDEFINED; Material: Gabião · pedra irregular
Pset_CasaProvenance - DesignSource: Casa Sobreposta / configuration.json; ReferenceFile: 260617_CasaDFL_Estrutura_Terreno.ifc; ConstructionBasis: DESIGN_ASSUMPTION; Note: R08 concept geometry; dimensions and connections not structurally verified.

# IfcBuildingElementProxy: Limite south · vala de interceção (46)
In: Lares · Rua das Mercês · artigo 4771
PredefinedType: USERDEFINED; Material: Brita drenante
Pset_CasaProvenance - DesignSource: Casa Sobreposta / configuration.json; ReferenceFile: 260617_CasaDFL_Estrutura_Terreno.ifc; ConstructionBasis: DESIGN_ASSUMPTION

# IfcBuildingElementProxy: Trepadeiras · floreira (10)
In: 00 · Habitação e estacionamento
PredefinedType: USERDEFINED; Material: Betão armado / Stahlbeton
Pset_CasaProvenance - DesignSource: Casa Sobreposta / configuration.json; ReferenceFile: 260617_CasaDFL_Estrutura_Terreno.ifc; ConstructionBasis: DESIGN_ASSUMPTION; Note: Indicative planter; soil volume, irrigation, root space and waterproofing to design.

# IfcColumn (48)
In: 00 · Habitação e estacionamento
Material: Betão armado / Stahlbeton
Pset_CasaProvenance - DesignSource: Casa Sobreposta / configuration.json; ReferenceFile: 260617_CasaDFL_Estrutura_Terreno.ifc
Name | ConstructionBasis
18 x Casa térrea · pedestal | ADAPTED_REFERENCE
24 x Pódio suspenso · apoio sobre o terreno | DESIGN_ASSUMPTION
6 x Varanda coberta · pedestal enterrado | DESIGN_ASSUMPTION

# IfcColumn: IPE240 / steel (18)
In: 00 · Habitação e estacionamento
Type - Material: Aço pintado / Stahl lackiert
Pset_CasaProvenance - DesignSource: Casa Sobreposta / configuration.json; ReferenceFile: 260617_CasaDFL_Estrutura_Terreno.ifc; ConstructionBasis: ADAPTED_REFERENCE; Note: Reference section; spans, stability and connections require design.

# IfcColumn: RHS80x60x4 / steel (4)
In: 00 · Habitação e estacionamento
Type - Material: Aço pintado / Stahl lackiert
Pset_CasaProvenance - DesignSource: Casa Sobreposta / configuration.json; ReferenceFile: 260617_CasaDFL_Estrutura_Terreno.ifc; ConstructionBasis: DESIGN_ASSUMPTION; Note: Reference section; spans, stability and connections require design.

# IfcColumn: TIMBER0.160x0.160 / timber (24)
In: 00 · Habitação e estacionamento
Type - Material: Madeira / Bauholz
Pset_CasaProvenance - DesignSource: Casa Sobreposta / configuration.json; ReferenceFile: 260617_CasaDFL_Estrutura_Terreno.ifc; ConstructionBasis: DESIGN_ASSUMPTION; Note: Visible timber concept; strength class, deflection, stability, wind and fire design pending.

# IfcCovering (15)
Pset_CasaProvenance - DesignSource: Casa Sobreposta / configuration.json; ReferenceFile: 260617_CasaDFL_Estrutura_Terreno.ifc; ConstructionBasis: DESIGN_ASSUMPTION
Name | In | PredefinedType | Material
2 x Cobertura · forro de madeira | 00 · Habitação e estacionamento | CLADDING | Madeira / Bauholz
2 x Cobertura · isolamento | 00 · Habitação e estacionamento | INSULATION | Lã mineral / Mineralwolle 2
2 x Cobertura · membrana | 00 · Habitação e estacionamento | MEMBRANE | Membrana impermeável — hipótese
Cobertura · telhas individualizadas 1 | 00 · Habitação e estacionamento | ROOFING | Telha cerâmica · tile0 | Pset_CasaProvenance - Note: R08 concept geometry; dimensions and connections not structurally verified.
Cobertura · telhas individualizadas 2 | 00 · Habitação e estacionamento | ROOFING | Telha cerâmica · tile1 | Pset_CasaProvenance - Note: R08 concept geometry; dimensions and connections not structurally verified.
Cobertura · telhas individualizadas 3 | 00 · Habitação e estacionamento | ROOFING | Telha cerâmica · tile2 | Pset_CasaProvenance - Note: R08 concept geometry; dimensions and connections not structurally verified.
Cobertura · cumeeira cerâmica | 00 · Habitação e estacionamento | ROOFING | Telha cerâmica · tile1
Cisterna · camada drenante 100 mm | -01 · Cisterna sob o terraço | FLOORING | Brita drenante
Cisterna · impermeabilização poente | -01 · Cisterna sob o terraço | MEMBRANE | Membrana impermeável — hipótese
Cisterna · impermeabilização norte | -01 · Cisterna sob o terraço | MEMBRANE | Membrana impermeável — hipótese
Cisterna · impermeabilização sul | -01 · Cisterna sob o terraço | MEMBRANE | Membrana impermeável — hipótese
Cisterna · impermeabilização nascente | -01 · Cisterna sob o terraço | MEMBRANE | Membrana impermeável — hipótese

# IfcDoor (18)
In: 00 · Habitação e estacionamento
PredefinedType: DOOR
Pset_CasaProvenance - DesignSource: Casa Sobreposta / configuration.json; ReferenceFile: 260617_CasaDFL_Estrutura_Terreno.ifc
Name | OverallHeight (m) | OverallWidth (m) | OperationType | Material | ConstructionBasis
Porta interior 1 | 2.1 | 0.830093 | SINGLE_SWING_LEFT | OSB | ADAPTED_REFERENCE
Porta interior 2 | 2.1 | 0.830093 | SINGLE_SWING_LEFT | OSB | ADAPTED_REFERENCE
Porta interior 3 | 2.1 | 0.730086 | SINGLE_SWING_LEFT | OSB | ADAPTED_REFERENCE
Porta interior 4 | 2.1 | 0.830092 | SINGLE_SWING_LEFT | OSB | ADAPTED_REFERENCE
Porta interior 5 | 2.1 | 0.830077 | SINGLE_SWING_LEFT | OSB | ADAPTED_REFERENCE
Porta interior 6 | 2.1 | 0.730017 | SINGLE_SWING_LEFT | OSB | ADAPTED_REFERENCE
Porta do estacionamento | 2.1 | 0.83 | SINGLE_SWING_LEFT | Aço pintado / Stahl lackiert | ADAPTED_REFERENCE
Folha de correr sul 2 | 3 | 1.97133 | SLIDING_TO_LEFT | Vidro / Normalglas | DESIGN_ASSUMPTION
Folha de correr sul 4 | 3 | 1.97133 | SLIDING_TO_LEFT | Vidro / Normalglas | DESIGN_ASSUMPTION
Folha de correr sul 6 | 3 | 1.97133 | SLIDING_TO_LEFT | Vidro / Normalglas | DESIGN_ASSUMPTION
Folha de correr sul 8 | 3 | 1.97133 | SLIDING_TO_LEFT | Vidro / Normalglas | DESIGN_ASSUMPTION
Folha de correr sul 10 | 3 | 1.97133 | SLIDING_TO_LEFT | Vidro / Normalglas | DESIGN_ASSUMPTION
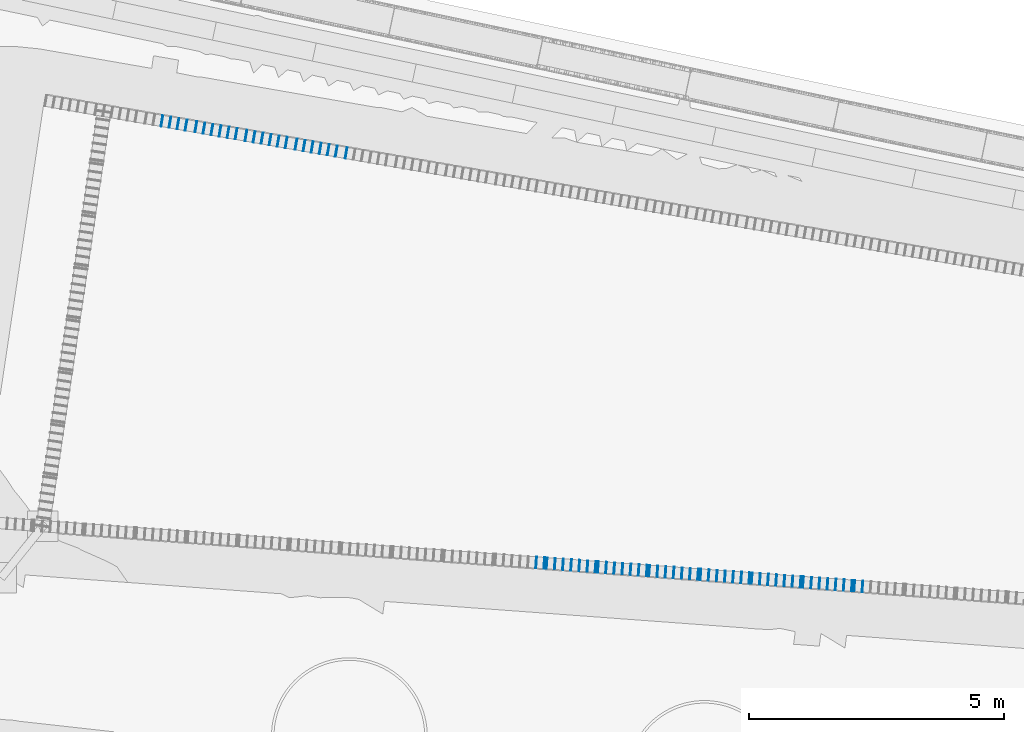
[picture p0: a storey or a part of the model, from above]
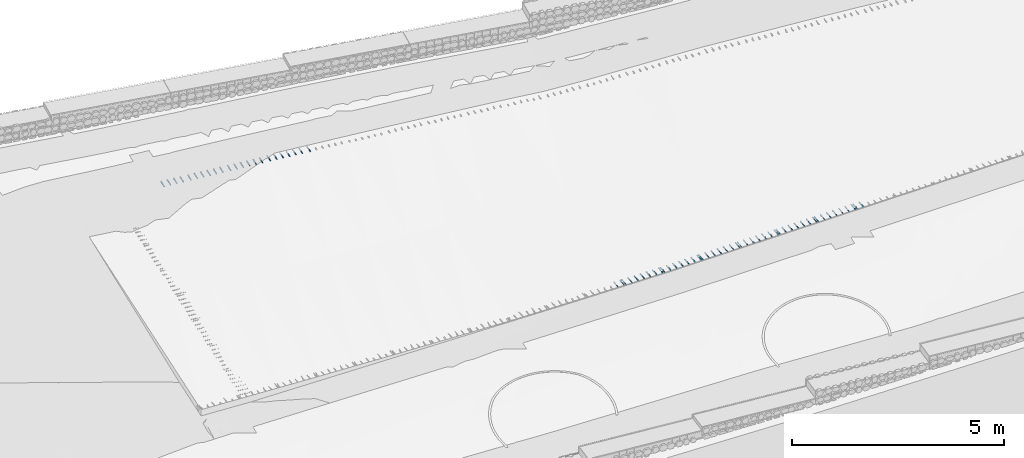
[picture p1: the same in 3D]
Properties of the parts of a building model (IFC4), part 3 of 3

# IfcWall: Limite south · gabião 6 · núcleo de pedra
Pset_CasaProvenance - DesignSource: Casa Sobreposta / configuration.json; ReferenceFile: 260617_CasaDFL_Estrutura_Terreno.ifc; ConstructionBasis: DESIGN_ASSUMPTION; Note: Concept gabion envelope; mesh gauge, foundation, filter and retaining capacity to design.
Pset_CasaBoundary - BaseSurveyLevel_m: 11; TopSurveyLevel_m: 12.1; Status: CONCEPT_NOT_SIZED

# IfcWall: Limite south · gabião 7 · núcleo de pedra
In: Lares · Rua das Mercês · artigo 4771
PredefinedType: USERDEFINED; Material: Gabião · enchimento
Pset_CasaProvenance - DesignSource: Casa Sobreposta / configuration.json; ReferenceFile: 260617_CasaDFL_Estrutura_Terreno.ifc; ConstructionBasis: DESIGN_ASSUMPTION; Note: Concept gabion envelope; mesh gauge, foundation, filter and retaining capacity to design.
Pset_CasaBoundary - BaseSurveyLevel_m: 11.25; TopSurveyLevel_m: 12.2; Status: CONCEPT_NOT_SIZED

# IfcWall: Limite south · gabião 8 · núcleo de pedra
In: Lares · Rua das Mercês · artigo 4771
PredefinedType: USERDEFINED; Material: Gabião · enchimento
Pset_CasaProvenance - DesignSource: Casa Sobreposta / configuration.json; ReferenceFile: 260617_CasaDFL_Estrutura_Terreno.ifc; ConstructionBasis: DESIGN_ASSUMPTION; Note: Concept gabion envelope; mesh gauge, foundation, filter and retaining capacity to design.
Pset_CasaBoundary - BaseSurveyLevel_m: 11.25; TopSurveyLevel_m: 12.4; Status: CONCEPT_NOT_SIZED

# IfcWall: Limite south · gabião 9 · núcleo de pedra
In: Lares · Rua das Mercês · artigo 4771
PredefinedType: USERDEFINED; Material: Gabião · enchimento
Pset_CasaProvenance - DesignSource: Casa Sobreposta / configuration.json; ReferenceFile: 260617_CasaDFL_Estrutura_Terreno.ifc; ConstructionBasis: DESIGN_ASSUMPTION; Note: Concept gabion envelope; mesh gauge, foundation, filter and retaining capacity to design.
Pset_CasaBoundary - BaseSurveyLevel_m: 11.5; TopSurveyLevel_m: 12.5; Status: CONCEPT_NOT_SIZED

# IfcWindow (10)
In: 00 · Habitação e estacionamento
PredefinedType: WINDOW; PartitioningType: SINGLE_PANEL; Material: Vidro / Normalglas
Pset_CasaProvenance - DesignSource: Casa Sobreposta / configuration.json; ReferenceFile: 260617_CasaDFL_Estrutura_Terreno.ifc; ConstructionBasis: DESIGN_ASSUMPTION
Name | OverallHeight (m) | OverallWidth (m)
Rasgo norte 1 | 0.3 | 3.79
Rasgo norte 2 | 0.3 | 3.79
Rasgo norte 3 | 0.3 | 3.79
Rasgo norte 4 | 0.3 | 3.79
Rasgo norte 5 | 0.3 | 3.79
Rasgo norte 6 | 0.3 | 3.79
Rasgo norte 7 | 0.3 | 0.71
Fachada poente integralmente envidraçada · módulo 1 | 3 | 1.55 | Pset_CasaGlazedFacade - Revision: R02 · kiwi pergola; Facade: WEST / highlighted end in user sketch; Infill: Full-height glazing; no opaque infill; GlazingSpecification: 8 mm nominal representation only; insulated safety glazing assembly to specify
Fachada poente integralmente envidraçada · módulo 2 | 3 | 1.55 | Pset_CasaGlazedFacade - Revision: R02 · kiwi pergola; Facade: WEST / highlighted end in user sketch; Infill: Full-height glazing; no opaque infill; GlazingSpecification: 8 mm nominal representation only; insulated safety glazing assembly to specify
Fachada poente integralmente envidraçada · módulo 3 | 3 | 1.55 | Pset_CasaGlazedFacade - Revision: R02 · kiwi pergola; Facade: WEST / highlighted end in user sketch; Infill: Full-height glazing; no opaque infill; GlazingSpecification: 8 mm nominal representation only; insulated safety glazing assembly to specify
